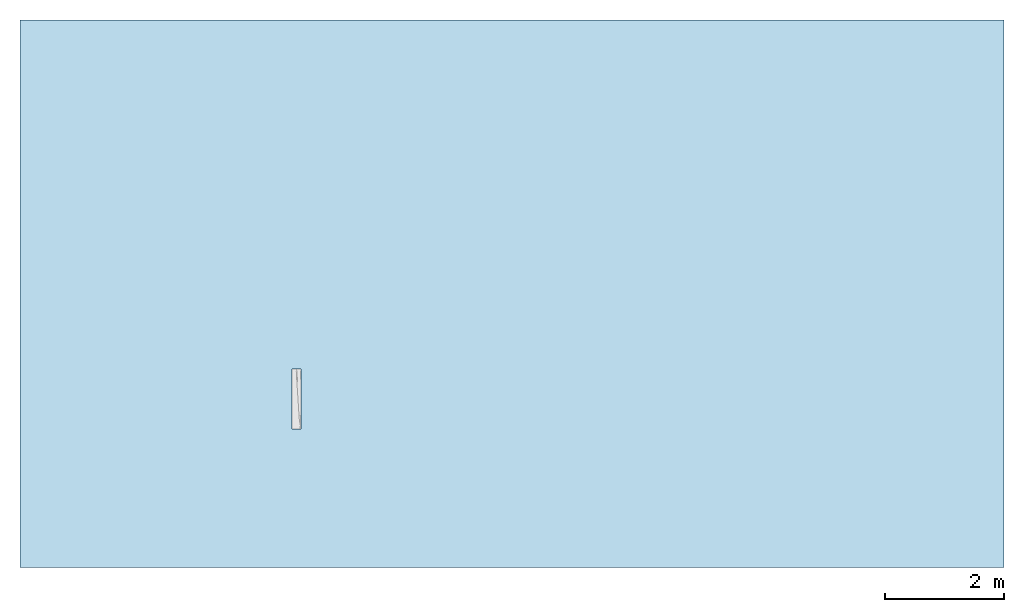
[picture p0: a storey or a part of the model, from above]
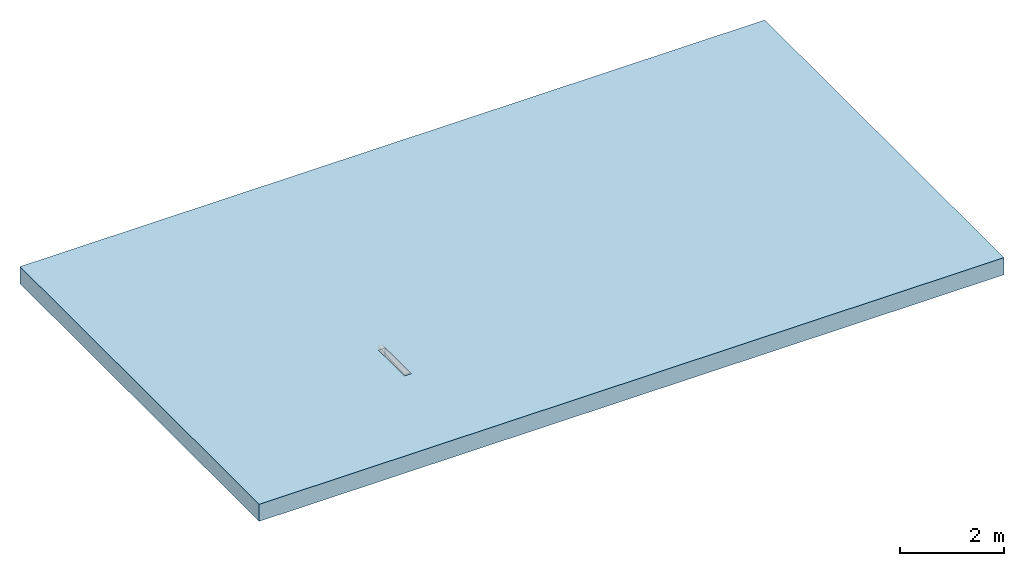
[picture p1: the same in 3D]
Properties of the parts of a building model (IFC2X3)

# File
Description: ViewDefinition [CoordinationView]
File name: 4244 - RH drop kerb - 1000mm LG.ifc
Time: 2013-09-02T12:23:03
Written by: Autodesk Revit 2013
Made in: 20120221_2030(x64)

# IfcProject, Project Number
LongName: Project Name; Phase: Project Status

# IfcSite, Default
RefLatitude: 42, 21, 30, 344238; RefLongitude: -71, -3, -35, -194702; RefElevation: 0 mm

# IfcBuilding
Pset_BuildingCommon - NumberOfStoreys: 1
Other - Project Status: Project Status; Project Name: Project Name; Client Name: Owner; Project Number: Project Number; Project Issue Date: Issue Date; Project Address: ## Street City, State Zip

# IfcBuildingStorey, Level 1
LongName: Level 1; Elevation: 0 mm
Constraints - Elevation Base: 0; Elevation: 0 mm
Graphics - Symbol at End 1 Default: no; Line Pattern: Center; Symbol at End 2 Default: yes; Color: 0; Symbol: M_Level Head - Circle: M_Level Head - Circle; Line Weight: 1
Dimensions - Computation Height: 0 mm
Identity Data - Structural: no; Name: Level 1; Building Story: yes

# IfcBuildingElementProxy: 4244 - RH drop kerb - 1000mm LG, Civil-Drainage-Channel-ACO-KerbDrain-SP380:4244 - RH drop kerb - 1000mm LG:4244 - RH drop kerb - 1000mm LG:308659
In: Level 1
Material: ACO Polymer Concrete.
Constraints - Level: Level: Level 1; Moves With Nearby Elements: no
Phasing - Phase Created: New Construction
Dimensions - Volume: 28619555 mm3; Endcap void: 2000 mm; Void Length: 1000 mm; Void Depth: -280 mm; Access hole: 2 mm; Void Width: 150 mm; AccessDepth: 2000 mm
Pset_BuildingElementProxyCommon - Reference: 4244 - RH drop kerb - 1000mm LG
General - SerialNumber: 0.000000; TagNumber: 0.000000
Identity Data - OmniClass Title: Rainwater Removal; Assembly Description: Rain Water Drainage; Assembly Code: D2040; e-mail Sales: customersupport@aco.co.uk; Product Page URL: http://www.aco.co.uk/product_detail.php?id=3; Product brochure: http://www.aco.co.uk/download.php?id=120; Installation guidelines: http://www.aco.co.uk/download.php?id=120; Address: ACO Business Park, Hitchin Road, Shefford, Bedfordshire, United Kingdom SG17 5TE; Cost: 0; Type Comments: ACO KerbDrain SP380 splayed right-hand drop kerb unit 1000mm long; Maintenance guidelines: http://www.aco.co.uk/download.php?id=120; Price: POA - contact ACO; Product Code: 4244; URL: www.aco.co.uk; OmniClass Number: 23.70.50.24; Telephone: +44 (0)1462 816666; Model Description: Combined kerb and drainage system; e-mail Technical: technical@aco.co.uk; Model: ACO KerbDrain SP380; Fax: +44 (0)1462 815895; Manufacturer: ACO Technologies plc - ACO Water Management Division
Data - Load Class: A 15 - D 400; Concrete Surround Volume - Load Class A 15 - D 400 - Concrete Pavement: N/A; Connection Pipe O.D: N/A; Channel C.S.A: 0.03 to 0.02mm²; Drainage Slot Width: N/A; Product Weight: 59.5 Kg; Drainage Slot Intake area: N/A; Invert Depth: 355/280mm; Installation - Concrete Grade: Refer to brochure; Product Standard: BS EN 1433:2002, CE marked, Kitemarked; Product Dimensions: 1000mm x 150mm x 380/305mm (LxWxH); Hydraulic Performance: http://www.aco.co.uk/download.php?id=120; ACO Hydraulic Design Software: http://www.acodesign.co.uk; Concrete Surround Volume - Load Class A 15 - D 400 - Grass or Asphalt Pavement: N/A
Construction - SP380 - 1000: no; LH transition unit: no; RH drop kerb: yes; Centre Stone: no; Closing end cap: no; LH inlet/outlet end cap: no; RH inlet/outlet end cap: no; SP380-500: no; LH drop kerb: no; Access Unit: no; RH transition unit: no
Green Building Properties - End Cap Recyclable: N/A; Channel Recycled Material Content: 20% minimum; Access Cover/Frame Recycled Material Content: N/A; End Cap Recycled Material Content: N/A; Channel Recyclable: Fully recyclable; Access Cover/Frame Recyclable: N/A
Materials and Finishes - Connection Pipe Material: N/A; Connection Pipe Material Colour: N/A; Access Cover/Frame Colour: N/A; End Cap Material: N/A; Access Cover/Frame Finish: N/A; Channel Colour: Grey; End Cap Colour: N/A; Access Cover/Frame Material: N/A; Channel Material: Vienite® Synthetic Resin Concrete
Other - CreatedBy: www.aco.co.uk; Revision: 1

# IfcOpeningElement: Recess (3)
In: Level 1
Dimensions - Perimeter: 51360 mm; Volume: 60546000000 mm3; Thickness: 400 mm; Area: 151470000 mm2
Phasing - Phase Created: New Construction
Constraints - Room Bounding: yes; Height Offset From Level: 0 mm; Related to Mass: no; Level: Level: Level 1
Structural - Enable Analytical Model: no; Structural: no
Construction - Default Thickness: 400 mm; Function: 0
Materials and Finishes - Structural Material: Plant
Graphics - Coarse Scale Fill Color: 0
Analytical Properties - Roughness: 1; Absorptance: 0.1

# IfcSlab: Floor:Generic Floor - 400mm, Floor:Generic Floor - 400mm:193825
In: Level 1
PredefinedType: FLOOR; Material: Plant 400 mm
Dimensions - Perimeter: 51360 mm; Volume: 60546000000 mm3; Thickness: 400 mm; Area: 151470000 mm2
Phasing - Phase Created: New Construction
Constraints - Room Bounding: yes; Height Offset From Level: 0 mm; Related to Mass: no; Level: Level: Level 1
Structural - Enable Analytical Model: no; Structural: no
Pset_SlabCommon - Reference: Generic Floor - 400mm; IsExternal: no; LoadBearing: yes
Construction - Default Thickness: 400 mm; Function: 0
Materials and Finishes - Structural Material: Plant
Graphics - Coarse Scale Fill Color: 0
Analytical Properties - Roughness: 1; Absorptance: 0.1
